VERSION 5.8 ;
BUSBITCHARS "[]" ;
DIVIDERCHAR "/" ;
UNITS
    DATABASE MICRONS 1000 ;
END UNITS

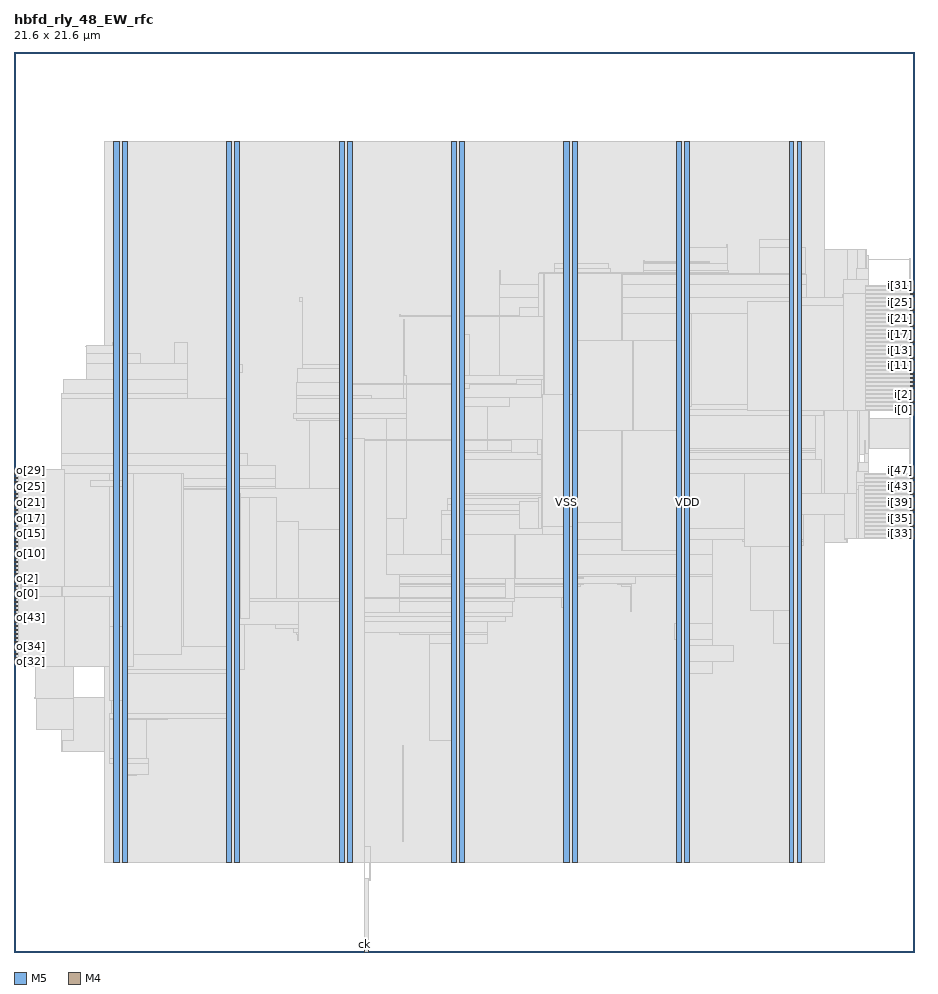
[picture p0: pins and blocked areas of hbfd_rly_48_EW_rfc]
MACRO hbfd_rly_48_EW_rfc
  FOREIGN hbfd_rly_48_EW_rfc 0 0 ;
  CLASS BLOCK ;
  SIZE 21.6 BY 21.6 ;
  PIN ck
    DIRECTION INPUT ;
    USE SIGNAL ;
    PORT
      LAYER M5 ;
        RECT  8.4 0 8.424 0.084 ;
    END
  END ck
  PIN i[0]
    DIRECTION INPUT ;
    USE SIGNAL ;
    PORT
      LAYER M4 ;
        RECT  21.516 13.008 21.6 13.032 ;
    END
  END i[0]
  PIN i[10]
    DIRECTION INPUT ;
    USE SIGNAL ;
    PORT
      LAYER M4 ;
        RECT  21.516 13.968 21.6 13.992 ;
    END
  END i[10]
  PIN i[11]
    DIRECTION INPUT ;
    USE SIGNAL ;
    PORT
      LAYER M4 ;
        RECT  21.516 14.064 21.6 14.088 ;
    END
  END i[11]
  PIN i[12]
    DIRECTION INPUT ;
    USE SIGNAL ;
    PORT
      LAYER M4 ;
        RECT  21.516 14.16 21.6 14.184 ;
    END
  END i[12]
  PIN i[13]
    DIRECTION INPUT ;
    USE SIGNAL ;
    PORT
      LAYER M4 ;
        RECT  21.516 14.256 21.6 14.28 ;
    END
  END i[13]
  PIN i[14]
    DIRECTION INPUT ;
    USE SIGNAL ;
    PORT
      LAYER M4 ;
        RECT  21.516 14.352 21.6 14.376 ;
    END
  END i[14]
  PIN i[15]
    DIRECTION INPUT ;
    USE SIGNAL ;
    PORT
      LAYER M4 ;
        RECT  21.516 14.448 21.6 14.472 ;
    END
  END i[15]
  PIN i[16]
    DIRECTION INPUT ;
    USE SIGNAL ;
    PORT
      LAYER M4 ;
        RECT  21.516 14.544 21.6 14.568 ;
    END
  END i[16]
  PIN i[17]
    DIRECTION INPUT ;
    USE SIGNAL ;
    PORT
      LAYER M4 ;
        RECT  21.516 14.64 21.6 14.664 ;
    END
  END i[17]
  PIN i[18]
    DIRECTION INPUT ;
    USE SIGNAL ;
    PORT
      LAYER M4 ;
        RECT  21.516 14.736 21.6 14.76 ;
    END
  END i[18]
  PIN i[19]
    DIRECTION INPUT ;
    USE SIGNAL ;
    PORT
      LAYER M4 ;
        RECT  21.516 14.832 21.6 14.856 ;
    END
  END i[19]
  PIN i[1]
    DIRECTION INPUT ;
    USE SIGNAL ;
    PORT
      LAYER M4 ;
        RECT  21.516 13.104 21.6 13.128 ;
    END
  END i[1]
  PIN i[20]
    DIRECTION INPUT ;
    USE SIGNAL ;
    PORT
      LAYER M4 ;
        RECT  21.516 14.928 21.6 14.952 ;
    END
  END i[20]
  PIN i[21]
    DIRECTION INPUT ;
    USE SIGNAL ;
    PORT
      LAYER M4 ;
        RECT  21.516 15.024 21.6 15.048 ;
    END
  END i[21]
  PIN i[22]
    DIRECTION INPUT ;
    USE SIGNAL ;
    PORT
      LAYER M4 ;
        RECT  21.516 15.12 21.6 15.144 ;
    END
  END i[22]
  PIN i[23]
    DIRECTION INPUT ;
    USE SIGNAL ;
    PORT
      LAYER M4 ;
        RECT  21.516 15.216 21.6 15.24 ;
    END
  END i[23]
  PIN i[24]
    DIRECTION INPUT ;
    USE SIGNAL ;
    PORT
      LAYER M4 ;
        RECT  21.516 15.312 21.6 15.336 ;
    END
  END i[24]
  PIN i[25]
    DIRECTION INPUT ;
    USE SIGNAL ;
    PORT
      LAYER M4 ;
        RECT  21.516 15.408 21.6 15.432 ;
    END
  END i[25]
  PIN i[26]
    DIRECTION INPUT ;
    USE SIGNAL ;
    PORT
      LAYER M4 ;
        RECT  21.516 15.504 21.6 15.528 ;
    END
  END i[26]
  PIN i[27]
    DIRECTION INPUT ;
    USE SIGNAL ;
    PORT
      LAYER M4 ;
        RECT  21.516 15.6 21.6 15.624 ;
    END
  END i[27]
  PIN i[28]
    DIRECTION INPUT ;
    USE SIGNAL ;
    PORT
      LAYER M4 ;
        RECT  21.516 15.696 21.6 15.72 ;
    END
  END i[28]
  PIN i[29]
    DIRECTION INPUT ;
    USE SIGNAL ;
    PORT
      LAYER M4 ;
        RECT  21.516 15.792 21.6 15.816 ;
    END
  END i[29]
  PIN i[2]
    DIRECTION INPUT ;
    USE SIGNAL ;
    PORT
      LAYER M4 ;
        RECT  21.516 13.2 21.6 13.224 ;
    END
  END i[2]
  PIN i[30]
    DIRECTION INPUT ;
    USE SIGNAL ;
    PORT
      LAYER M4 ;
        RECT  21.516 15.888 21.6 15.912 ;
    END
  END i[30]
  PIN i[31]
    DIRECTION INPUT ;
    USE SIGNAL ;
    PORT
      LAYER M4 ;
        RECT  21.516 15.984 21.6 16.008 ;
    END
  END i[31]
  PIN i[32]
    DIRECTION INPUT ;
    USE SIGNAL ;
    PORT
      LAYER M4 ;
        RECT  21.516 9.936 21.6 9.96 ;
    END
  END i[32]
  PIN i[33]
    DIRECTION INPUT ;
    USE SIGNAL ;
    PORT
      LAYER M4 ;
        RECT  21.516 10.032 21.6 10.056 ;
    END
  END i[33]
  PIN i[34]
    DIRECTION INPUT ;
    USE SIGNAL ;
    PORT
      LAYER M4 ;
        RECT  21.516 10.128 21.6 10.152 ;
    END
  END i[34]
  PIN i[35]
    DIRECTION INPUT ;
    USE SIGNAL ;
    PORT
      LAYER M4 ;
        RECT  21.516 10.224 21.6 10.248 ;
    END
  END i[35]
  PIN i[36]
    DIRECTION INPUT ;
    USE SIGNAL ;
    PORT
      LAYER M4 ;
        RECT  21.516 10.32 21.6 10.344 ;
    END
  END i[36]
  PIN i[37]
    DIRECTION INPUT ;
    USE SIGNAL ;
    PORT
      LAYER M4 ;
        RECT  21.516 10.416 21.6 10.44 ;
    END
  END i[37]
  PIN i[38]
    DIRECTION INPUT ;
    USE SIGNAL ;
    PORT
      LAYER M4 ;
        RECT  21.516 10.512 21.6 10.536 ;
    END
  END i[38]
  PIN i[39]
    DIRECTION INPUT ;
    USE SIGNAL ;
    PORT
      LAYER M4 ;
        RECT  21.516 10.608 21.6 10.632 ;
    END
  END i[39]
  PIN i[3]
    DIRECTION INPUT ;
    USE SIGNAL ;
    PORT
      LAYER M4 ;
        RECT  21.516 13.296 21.6 13.32 ;
    END
  END i[3]
  PIN i[40]
    DIRECTION INPUT ;
    USE SIGNAL ;
    PORT
      LAYER M4 ;
        RECT  21.516 10.704 21.6 10.728 ;
    END
  END i[40]
  PIN i[41]
    DIRECTION INPUT ;
    USE SIGNAL ;
    PORT
      LAYER M4 ;
        RECT  21.516 10.8 21.6 10.824 ;
    END
  END i[41]
  PIN i[42]
    DIRECTION INPUT ;
    USE SIGNAL ;
    PORT
      LAYER M4 ;
        RECT  21.516 10.896 21.6 10.92 ;
    END
  END i[42]
  PIN i[43]
    DIRECTION INPUT ;
    USE SIGNAL ;
    PORT
      LAYER M4 ;
        RECT  21.516 10.992 21.6 11.016 ;
    END
  END i[43]
  PIN i[44]
    DIRECTION INPUT ;
    USE SIGNAL ;
    PORT
      LAYER M4 ;
        RECT  21.516 11.088 21.6 11.112 ;
    END
  END i[44]
  PIN i[45]
    DIRECTION INPUT ;
    USE SIGNAL ;
    PORT
      LAYER M4 ;
        RECT  21.516 11.184 21.6 11.208 ;
    END
  END i[45]
  PIN i[46]
    DIRECTION INPUT ;
    USE SIGNAL ;
    PORT
      LAYER M4 ;
        RECT  21.516 11.28 21.6 11.304 ;
    END
  END i[46]
  PIN i[47]
    DIRECTION INPUT ;
    USE SIGNAL ;
    PORT
      LAYER M4 ;
        RECT  21.516 11.376 21.6 11.4 ;
    END
  END i[47]
  PIN i[4]
    DIRECTION INPUT ;
    USE SIGNAL ;
    PORT
      LAYER M4 ;
        RECT  21.516 13.392 21.6 13.416 ;
    END
  END i[4]
  PIN i[5]
    DIRECTION INPUT ;
    USE SIGNAL ;
    PORT
      LAYER M4 ;
        RECT  21.516 13.488 21.6 13.512 ;
    END
  END i[5]
  PIN i[6]
    DIRECTION INPUT ;
    USE SIGNAL ;
    PORT
      LAYER M4 ;
        RECT  21.516 13.584 21.6 13.608 ;
    END
  END i[6]
  PIN i[7]
    DIRECTION INPUT ;
    USE SIGNAL ;
    PORT
      LAYER M4 ;
        RECT  21.516 13.68 21.6 13.704 ;
    END
  END i[7]
  PIN i[8]
    DIRECTION INPUT ;
    USE SIGNAL ;
    PORT
      LAYER M4 ;
        RECT  21.516 13.776 21.6 13.8 ;
    END
  END i[8]
  PIN i[9]
    DIRECTION INPUT ;
    USE SIGNAL ;
    PORT
      LAYER M4 ;
        RECT  21.516 13.872 21.6 13.896 ;
    END
  END i[9]
  PIN o[0]
    DIRECTION OUTPUT ;
    USE SIGNAL ;
    PORT
      LAYER M4 ;
        RECT  0 8.592 0.084 8.616 ;
    END
  END o[0]
  PIN o[10]
    DIRECTION OUTPUT ;
    USE SIGNAL ;
    PORT
      LAYER M4 ;
        RECT  0 9.552 0.084 9.576 ;
    END
  END o[10]
  PIN o[11]
    DIRECTION OUTPUT ;
    USE SIGNAL ;
    PORT
      LAYER M4 ;
        RECT  0 9.648 0.084 9.672 ;
    END
  END o[11]
  PIN o[12]
    DIRECTION OUTPUT ;
    USE SIGNAL ;
    PORT
      LAYER M4 ;
        RECT  0 9.744 0.084 9.768 ;
    END
  END o[12]
  PIN o[13]
    DIRECTION OUTPUT ;
    USE SIGNAL ;
    PORT
      LAYER M4 ;
        RECT  0 9.84 0.084 9.864 ;
    END
  END o[13]
  PIN o[14]
    DIRECTION OUTPUT ;
    USE SIGNAL ;
    PORT
      LAYER M4 ;
        RECT  0 9.936 0.084 9.96 ;
    END
  END o[14]
  PIN o[15]
    DIRECTION OUTPUT ;
    USE SIGNAL ;
    PORT
      LAYER M4 ;
        RECT  0 10.032 0.084 10.056 ;
    END
  END o[15]
  PIN o[16]
    DIRECTION OUTPUT ;
    USE SIGNAL ;
    PORT
      LAYER M4 ;
        RECT  0 10.128 0.084 10.152 ;
    END
  END o[16]
  PIN o[17]
    DIRECTION OUTPUT ;
    USE SIGNAL ;
    PORT
      LAYER M4 ;
        RECT  0 10.224 0.084 10.248 ;
    END
  END o[17]
  PIN o[18]
    DIRECTION OUTPUT ;
    USE SIGNAL ;
    PORT
      LAYER M4 ;
        RECT  0 10.32 0.084 10.344 ;
    END
  END o[18]
  PIN o[19]
    DIRECTION OUTPUT ;
    USE SIGNAL ;
    PORT
      LAYER M4 ;
        RECT  0 10.416 0.084 10.44 ;
    END
  END o[19]
  PIN o[1]
    DIRECTION OUTPUT ;
    USE SIGNAL ;
    PORT
      LAYER M4 ;
        RECT  0 8.688 0.084 8.712 ;
    END
  END o[1]
  PIN o[20]
    DIRECTION OUTPUT ;
    USE SIGNAL ;
    PORT
      LAYER M4 ;
        RECT  0 10.512 0.084 10.536 ;
    END
  END o[20]
  PIN o[21]
    DIRECTION OUTPUT ;
    USE SIGNAL ;
    PORT
      LAYER M4 ;
        RECT  0 10.608 0.084 10.632 ;
    END
  END o[21]
  PIN o[22]
    DIRECTION OUTPUT ;
    USE SIGNAL ;
    PORT
      LAYER M4 ;
        RECT  0 10.704 0.084 10.728 ;
    END
  END o[22]
  PIN o[23]
    DIRECTION OUTPUT ;
    USE SIGNAL ;
    PORT
      LAYER M4 ;
        RECT  0 10.8 0.084 10.824 ;
    END
  END o[23]
  PIN o[24]
    DIRECTION OUTPUT ;
    USE SIGNAL ;
    PORT
      LAYER M4 ;
        RECT  0 10.896 0.084 10.92 ;
    END
  END o[24]
  PIN o[25]
    DIRECTION OUTPUT ;
    USE SIGNAL ;
    PORT
      LAYER M4 ;
        RECT  0 10.992 0.084 11.016 ;
    END
  END o[25]
  PIN o[26]
    DIRECTION OUTPUT ;
    USE SIGNAL ;
    PORT
      LAYER M4 ;
        RECT  0 11.088 0.084 11.112 ;
    END
  END o[26]
  PIN o[27]
    DIRECTION OUTPUT ;
    USE SIGNAL ;
    PORT
      LAYER M4 ;
        RECT  0 11.184 0.084 11.208 ;
    END
  END o[27]
  PIN o[28]
    DIRECTION OUTPUT ;
    USE SIGNAL ;
    PORT
      LAYER M4 ;
        RECT  0 11.28 0.084 11.304 ;
    END
  END o[28]
  PIN o[29]
    DIRECTION OUTPUT ;
    USE SIGNAL ;
    PORT
      LAYER M4 ;
        RECT  0 11.376 0.084 11.4 ;
    END
  END o[29]
  PIN o[2]
    DIRECTION OUTPUT ;
    USE SIGNAL ;
    PORT
      LAYER M4 ;
        RECT  0 8.784 0.084 8.808 ;
    END
  END o[2]
  PIN o[30]
    DIRECTION OUTPUT ;
    USE SIGNAL ;
    PORT
      LAYER M4 ;
        RECT  0 11.472 0.084 11.496 ;
    END
  END o[30]
  PIN o[31]
    DIRECTION OUTPUT ;
    USE SIGNAL ;
    PORT
      LAYER M4 ;
        RECT  0 11.568 0.084 11.592 ;
    END
  END o[31]
  PIN o[32]
    DIRECTION OUTPUT ;
    USE SIGNAL ;
    PORT
      LAYER M4 ;
        RECT  0 6.96 0.084 6.984 ;
    END
  END o[32]
  PIN o[33]
    DIRECTION OUTPUT ;
    USE SIGNAL ;
    PORT
      LAYER M4 ;
        RECT  0 7.056 0.084 7.08 ;
    END
  END o[33]
  PIN o[34]
    DIRECTION OUTPUT ;
    USE SIGNAL ;
    PORT
      LAYER M4 ;
        RECT  0 7.152 0.084 7.176 ;
    END
  END o[34]
  PIN o[35]
    DIRECTION OUTPUT ;
    USE SIGNAL ;
    PORT
      LAYER M4 ;
        RECT  0 7.248 0.084 7.272 ;
    END
  END o[35]
  PIN o[36]
    DIRECTION OUTPUT ;
    USE SIGNAL ;
    PORT
      LAYER M4 ;
        RECT  0 7.344 0.084 7.368 ;
    END
  END o[36]
  PIN o[37]
    DIRECTION OUTPUT ;
    USE SIGNAL ;
    PORT
      LAYER M4 ;
        RECT  0 7.44 0.084 7.464 ;
    END
  END o[37]
  PIN o[38]
    DIRECTION OUTPUT ;
    USE SIGNAL ;
    PORT
      LAYER M4 ;
        RECT  0 7.536 0.084 7.56 ;
    END
  END o[38]
  PIN o[39]
    DIRECTION OUTPUT ;
    USE SIGNAL ;
    PORT
      LAYER M4 ;
        RECT  0 7.632 0.084 7.656 ;
    END
  END o[39]
  PIN o[3]
    DIRECTION OUTPUT ;
    USE SIGNAL ;
    PORT
      LAYER M4 ;
        RECT  0 8.88 0.084 8.904 ;
    END
  END o[3]
  PIN o[40]
    DIRECTION OUTPUT ;
    USE SIGNAL ;
    PORT
      LAYER M4 ;
        RECT  0 7.728 0.084 7.752 ;
    END
  END o[40]
  PIN o[41]
    DIRECTION OUTPUT ;
    USE SIGNAL ;
    PORT
      LAYER M4 ;
        RECT  0 7.824 0.084 7.848 ;
    END
  END o[41]
  PIN o[42]
    DIRECTION OUTPUT ;
    USE SIGNAL ;
    PORT
      LAYER M4 ;
        RECT  0 7.92 0.084 7.944 ;
    END
  END o[42]
  PIN o[43]
    DIRECTION OUTPUT ;
    USE SIGNAL ;
    PORT
      LAYER M4 ;
        RECT  0 8.016 0.084 8.04 ;
    END
  END o[43]
  PIN o[44]
    DIRECTION OUTPUT ;
    USE SIGNAL ;
    PORT
      LAYER M4 ;
        RECT  0 8.112 0.084 8.136 ;
    END
  END o[44]
  PIN o[45]
    DIRECTION OUTPUT ;
    USE SIGNAL ;
    PORT
      LAYER M4 ;
        RECT  0 8.208 0.084 8.232 ;
    END
  END o[45]
  PIN o[46]
    DIRECTION OUTPUT ;
    USE SIGNAL ;
    PORT
      LAYER M4 ;
        RECT  0 8.304 0.084 8.328 ;
    END
  END o[46]
  PIN o[47]
    DIRECTION OUTPUT ;
    USE SIGNAL ;
    PORT
      LAYER M4 ;
        RECT  0 8.4 0.084 8.424 ;
    END
  END o[47]
  PIN o[4]
    DIRECTION OUTPUT ;
    USE SIGNAL ;
    PORT
      LAYER M4 ;
        RECT  0 8.976 0.084 9 ;
    END
  END o[4]
  PIN o[5]
    DIRECTION OUTPUT ;
    USE SIGNAL ;
    PORT
      LAYER M4 ;
        RECT  0 9.072 0.084 9.096 ;
    END
  END o[5]
  PIN o[6]
    DIRECTION OUTPUT ;
    USE SIGNAL ;
    PORT
      LAYER M4 ;
        RECT  0 9.168 0.084 9.192 ;
    END
  END o[6]
  PIN o[7]
    DIRECTION OUTPUT ;
    USE SIGNAL ;
    PORT
      LAYER M4 ;
        RECT  0 9.264 0.084 9.288 ;
    END
  END o[7]
  PIN o[8]
    DIRECTION OUTPUT ;
    USE SIGNAL ;
    PORT
      LAYER M4 ;
        RECT  0 9.36 0.084 9.384 ;
    END
  END o[8]
  PIN o[9]
    DIRECTION OUTPUT ;
    USE SIGNAL ;
    PORT
      LAYER M4 ;
        RECT  0 9.456 0.084 9.48 ;
    END
  END o[9]
  PIN rfi
    DIRECTION INPUT ;
    USE SIGNAL ;
    PORT
      LAYER M4 ;
        RECT  21.516 11.472 21.6 11.496 ;
    END
  END rfi
  PIN rfo
    DIRECTION OUTPUT ;
    USE SIGNAL ;
    PORT
      LAYER M4 ;
        RECT  0 8.496 0.084 8.52 ;
    END
  END rfo
  PIN rs
    DIRECTION INPUT ;
    USE SIGNAL ;
    PORT
      LAYER M5 ;
        RECT  8.496 0 8.52 0.084 ;
    END
  END rs
  PIN VDD
    DIRECTION INOUT ;
    USE POWER ;
    PORT
      LAYER M5 ;
        RECT  18.792 2.151 18.912 19.449 ;
        RECT  16.092 2.151 16.212 19.449 ;
        RECT  13.392 2.151 13.512 19.449 ;
        RECT  10.692 2.151 10.812 19.449 ;
        RECT  7.992 2.151 8.112 19.449 ;
        RECT  5.292 2.151 5.412 19.449 ;
        RECT  2.592 2.151 2.712 19.449 ;
    END
  END VDD
  PIN VSS
    DIRECTION INOUT ;
    USE GROUND ;
    PORT
      LAYER M5 ;
        RECT  18.6 2.137 18.72 19.463 ;
        RECT  15.9 2.137 16.02 19.463 ;
        RECT  13.2 2.137 13.32 19.463 ;
        RECT  10.5 2.137 10.62 19.463 ;
        RECT  7.8 2.137 7.92 19.463 ;
        RECT  5.1 2.137 5.22 19.463 ;
        RECT  2.4 2.137 2.52 19.463 ;
    END
  END VSS
  # OT_OBS_CLOSED layer=M5 d_um=1.536 added=8
  OBS
    LAYER RVTN ;
     RECT  2.16 2.16 19.44 2.295 ;
     RECT  2.16 2.565 19.44 2.835 ;
     RECT  2.16 3.105 19.44 3.375 ;
     RECT  2.16 3.645 19.44 3.915 ;
     RECT  2.16 4.185 19.44 4.455 ;
     RECT  2.16 4.725 19.44 4.995 ;
     RECT  2.16 5.265 19.44 5.535 ;
     RECT  2.16 5.805 19.44 6.075 ;
     RECT  2.16 6.345 19.44 6.615 ;
     RECT  2.16 6.885 19.44 7.155 ;
     RECT  2.16 7.425 19.44 7.695 ;
     RECT  2.16 7.965 19.44 8.235 ;
     RECT  2.16 8.505 19.44 8.775 ;
     RECT  2.16 9.045 19.44 9.315 ;
     RECT  2.16 9.585 19.44 9.855 ;
     RECT  2.16 10.125 19.44 10.395 ;
     RECT  2.16 10.665 19.44 10.935 ;
     RECT  2.16 11.205 19.44 11.475 ;
     RECT  2.16 11.745 19.44 12.015 ;
     RECT  2.16 12.285 19.44 12.555 ;
     RECT  2.16 12.825 19.44 13.095 ;
     RECT  2.16 13.365 19.44 13.635 ;
     RECT  2.16 13.905 19.44 14.175 ;
     RECT  2.16 14.445 19.44 14.715 ;
     RECT  2.16 14.985 19.44 15.255 ;
     RECT  2.16 15.525 19.44 15.795 ;
     RECT  2.16 16.065 19.44 16.335 ;
     RECT  2.16 16.605 19.44 16.875 ;
     RECT  2.16 17.145 19.44 17.415 ;
     RECT  2.16 17.685 19.44 17.955 ;
     RECT  2.16 18.225 19.44 18.495 ;
     RECT  2.16 18.765 19.44 19.035 ;
     RECT  2.16 19.305 19.44 19.44 ;
    LAYER RVTP ;
     RECT  2.16 2.295 19.44 2.565 ;
     RECT  2.16 2.835 19.44 3.105 ;
     RECT  2.16 3.375 19.44 3.645 ;
     RECT  2.16 3.915 19.44 4.185 ;
     RECT  2.16 4.455 19.44 4.725 ;
     RECT  2.16 4.995 19.44 5.265 ;
     RECT  2.16 5.535 19.44 5.805 ;
     RECT  2.16 6.075 19.44 6.345 ;
     RECT  2.16 6.615 19.44 6.885 ;
     RECT  2.16 7.155 19.44 7.425 ;
     RECT  2.16 7.695 19.44 7.965 ;
     RECT  2.16 8.235 19.44 8.505 ;
     RECT  2.16 8.775 19.44 9.045 ;
     RECT  2.16 9.315 19.44 9.585 ;
     RECT  2.16 9.855 19.44 10.125 ;
     RECT  2.16 10.395 19.44 10.665 ;
     RECT  2.16 10.935 19.44 11.205 ;
     RECT  2.16 11.475 19.44 11.745 ;
     RECT  2.16 12.015 19.44 12.285 ;
     RECT  2.16 12.555 19.44 12.825 ;
     RECT  2.16 13.095 19.44 13.365 ;
     RECT  2.16 13.635 19.44 13.905 ;
     RECT  2.16 14.175 19.44 14.445 ;
     RECT  2.16 14.715 19.44 14.985 ;
     RECT  2.16 15.255 19.44 15.525 ;
     RECT  2.16 15.795 19.44 16.065 ;
     RECT  2.16 16.335 19.44 16.605 ;
     RECT  2.16 16.875 19.44 17.145 ;
     RECT  2.16 17.415 19.44 17.685 ;
     RECT  2.16 17.955 19.44 18.225 ;
     RECT  2.16 18.495 19.44 18.765 ;
     RECT  2.16 19.035 19.44 19.305 ;
    LAYER M1 ;
     RECT  2.16 2.151 19.44 19.449 ;
    LAYER M2 ;
     RECT  0.103 8.208 0.139 8.496 ;
     RECT  0.103 10.836 0.203 10.854 ;
     RECT  0.139 8.136 0.239 8.874 ;
     RECT  0.319 9.486 0.419 9.504 ;
     RECT  0.499 6.084 0.535 6.102 ;
     RECT  0.535 5.346 1.147 6.102 ;
     RECT  1.147 13.374 1.183 13.392 ;
     RECT  0.239 8.136 1.255 8.496 ;
     RECT  1.399 12.366 1.471 12.384 ;
     RECT  1.147 4.806 2.16 6.102 ;
     RECT  1.255 7.668 2.16 8.496 ;
     RECT  1.471 12.33 2.16 12.384 ;
     RECT  1.183 13.374 2.16 13.734 ;
     RECT  1.723 14.526 2.16 14.544 ;
     RECT  2.16 2.151 19.44 19.449 ;
     RECT  19.44 9.828 20.003 16.866 ;
     RECT  20.003 10.098 20.255 16.866 ;
     RECT  20.255 10.098 20.291 13.086 ;
     RECT  20.291 10.098 20.435 11.196 ;
     RECT  20.255 14.148 20.435 16.866 ;
     RECT  20.435 10.17 20.471 10.926 ;
     RECT  20.435 16.614 20.471 16.866 ;
     RECT  20.471 10.17 20.507 10.386 ;
     RECT  20.291 11.952 20.507 13.086 ;
     RECT  20.435 14.148 20.507 14.976 ;
     RECT  20.471 16.614 20.507 16.704 ;
     RECT  20.507 12.096 20.543 13.086 ;
     RECT  20.543 12.096 21.515 12.816 ;
     RECT  20.507 16.614 21.515 16.632 ;
    LAYER M3 ;
     RECT  8.532 1.723 8.55 2.143 ;
     RECT  2.415 2.143 2.505 2.413 ;
     RECT  5.115 2.143 5.205 2.413 ;
     RECT  10.515 2.143 10.605 2.413 ;
     RECT  13.215 2.143 13.305 2.413 ;
     RECT  15.915 2.143 16.005 2.413 ;
     RECT  18.615 2.143 18.705 2.413 ;
     RECT  7.815 2.143 8.55 2.525 ;
     RECT  2.415 2.413 2.697 4.225 ;
     RECT  2.415 4.225 2.934 4.261 ;
     RECT  2.415 4.261 3.222 4.531 ;
     RECT  2.304 4.531 3.222 4.649 ;
     RECT  9.324 2.641 9.342 4.955 ;
     RECT  1.152 4.801 1.17 5.071 ;
     RECT  10.515 2.413 10.797 5.071 ;
     RECT  1.152 5.071 1.422 5.341 ;
     RECT  2.304 4.649 3.186 5.575 ;
     RECT  2.304 5.575 3.69 5.611 ;
     RECT  5.115 2.413 5.397 5.611 ;
     RECT  2.304 5.611 5.397 5.729 ;
     RECT  0.54 5.341 1.422 6.079 ;
     RECT  2.34 5.729 5.397 6.691 ;
     RECT  15.915 2.413 16.197 6.691 ;
     RECT  2.304 6.691 5.397 6.781 ;
     RECT  0.504 6.079 1.422 6.859 ;
     RECT  15.915 6.691 16.758 6.961 ;
     RECT  0.108 6.859 1.422 6.989 ;
     RECT  0.504 6.989 1.422 7.277 ;
     RECT  15.915 6.961 17.262 7.349 ;
     RECT  9.972 5.071 10.797 7.393 ;
     RECT  18.615 2.413 18.897 7.393 ;
     RECT  15.915 7.349 16.758 7.501 ;
     RECT  6.804 7.465 6.822 7.627 ;
     RECT  9.972 7.393 11.358 7.627 ;
     RECT  1.26 7.277 1.422 7.663 ;
     RECT  6.768 7.627 6.822 7.663 ;
     RECT  7.815 2.525 8.097 7.663 ;
     RECT  9.252 7.627 11.358 7.663 ;
     RECT  1.26 7.663 1.458 7.709 ;
     RECT  6.696 7.663 6.822 7.771 ;
     RECT  0.504 7.277 0.522 7.853 ;
     RECT  2.304 6.781 5.526 7.861 ;
     RECT  6.264 7.771 6.822 7.861 ;
     RECT  15.84 7.501 16.758 7.889 ;
     RECT  7.815 7.663 11.358 7.933 ;
     RECT  7.815 7.933 11.79 8.041 ;
     RECT  7.815 8.041 11.97 8.159 ;
     RECT  0.144 8.107 0.198 8.188 ;
     RECT  18.216 7.393 18.897 8.203 ;
     RECT  1.26 7.709 1.422 8.251 ;
     RECT  13.215 2.413 13.497 8.275 ;
     RECT  2.304 7.861 6.822 8.401 ;
     RECT  7.815 8.159 8.097 8.401 ;
     RECT  9.252 8.159 11.97 8.401 ;
     RECT  1.152 8.251 1.422 8.477 ;
     RECT  9.252 8.401 12.006 8.509 ;
     RECT  13.14 8.275 13.497 8.509 ;
     RECT  1.26 8.477 1.422 8.621 ;
     RECT  0.108 8.188 0.198 8.683 ;
     RECT  9.252 8.509 13.497 8.779 ;
     RECT  14.796 8.167 14.814 8.779 ;
     RECT  1.26 8.621 1.278 8.813 ;
     RECT  9.252 8.779 13.59 8.815 ;
     RECT  14.58 8.779 14.814 8.815 ;
     RECT  9.252 8.815 13.662 8.851 ;
     RECT  14.472 8.815 14.814 8.851 ;
     RECT  9.252 8.851 14.922 9.013 ;
     RECT  15.915 7.889 16.758 9.013 ;
     RECT  9.252 9.013 16.758 9.049 ;
     RECT  2.304 8.401 8.097 9.163 ;
     RECT  2.268 9.163 8.097 9.239 ;
     RECT  0.108 8.683 0.342 9.481 ;
     RECT  0.108 9.481 0.414 9.533 ;
     RECT  8.928 9.049 16.758 9.545 ;
     RECT  0.108 9.533 0.342 9.581 ;
     RECT  0.324 9.581 0.342 9.677 ;
     RECT  17.676 8.203 18.897 9.739 ;
     RECT  17.532 9.739 18.897 9.751 ;
     RECT  17.532 9.751 18.954 9.859 ;
     RECT  10.26 9.545 16.758 9.895 ;
     RECT  17.496 9.859 18.954 9.895 ;
     RECT  19.98 9.823 19.998 9.895 ;
     RECT  19.944 9.895 19.998 10.027 ;
     RECT  19.944 10.027 20.43 10.123 ;
     RECT  1.404 9.931 1.422 10.219 ;
     RECT  19.944 10.123 20.502 10.391 ;
     RECT  8.928 9.545 9.342 10.399 ;
     RECT  10.26 9.895 18.954 10.507 ;
     RECT  19.944 10.391 20.466 10.507 ;
     RECT  10.26 10.507 20.466 10.589 ;
     RECT  10.404 10.589 20.466 10.733 ;
     RECT  0.144 10.651 0.162 10.828 ;
     RECT  10.404 10.733 19.494 10.895 ;
     RECT  10.515 10.895 19.494 10.967 ;
     RECT  10.515 10.967 19.422 11.003 ;
     RECT  0.108 10.828 0.198 11.117 ;
     RECT  2.304 9.239 8.097 11.129 ;
     RECT  0.18 11.117 0.198 11.165 ;
     RECT  1.404 10.219 1.494 11.179 ;
     RECT  2.304 11.129 6.282 11.179 ;
     RECT  20.232 10.733 20.466 11.275 ;
     RECT  1.404 11.179 6.282 11.371 ;
     RECT  20.232 11.275 20.502 11.543 ;
     RECT  1.152 11.371 6.282 11.669 ;
     RECT  20.268 11.543 20.502 11.741 ;
     RECT  10.515 11.003 19.386 11.813 ;
     RECT  1.152 11.669 5.598 11.975 ;
     RECT  20.412 11.741 20.502 11.975 ;
     RECT  10.515 11.813 19.242 11.981 ;
     RECT  10.515 11.981 11.97 12.029 ;
     RECT  12.744 11.981 19.242 12.047 ;
     RECT  12.816 12.047 19.242 12.083 ;
     RECT  20.412 11.975 20.43 12.281 ;
     RECT  7.092 11.129 8.097 12.757 ;
     RECT  6.768 12.757 8.097 12.793 ;
     RECT  8.928 10.399 9.414 12.793 ;
     RECT  13.104 12.083 19.242 12.865 ;
     RECT  6.696 12.793 9.414 12.929 ;
     RECT  13.104 12.865 19.422 13.027 ;
     RECT  10.515 12.029 11.358 13.099 ;
     RECT  21.492 11.371 21.51 13.133 ;
     RECT  12.924 13.027 19.422 13.147 ;
     RECT  20.52 13.063 20.538 13.195 ;
     RECT  1.152 11.975 5.397 13.289 ;
     RECT  6.768 12.929 9.414 13.289 ;
     RECT  12.744 13.147 19.422 13.291 ;
     RECT  20.232 13.195 20.538 13.291 ;
     RECT  10.515 13.099 11.898 13.297 ;
     RECT  12.744 13.291 20.538 13.297 ;
     RECT  6.768 13.289 8.586 13.361 ;
     RECT  1.152 13.289 4.158 13.397 ;
     RECT  10.515 13.297 20.538 13.613 ;
     RECT  6.768 13.361 8.097 13.667 ;
     RECT  1.188 13.397 4.158 13.739 ;
     RECT  9.36 13.289 9.414 13.829 ;
     RECT  10.515 13.613 20.502 13.829 ;
     RECT  5.115 13.289 5.397 13.909 ;
     RECT  6.804 13.667 8.097 14.009 ;
     RECT  5.115 13.909 5.49 14.099 ;
     RECT  6.912 14.009 8.097 14.099 ;
     RECT  1.728 13.739 4.158 14.135 ;
     RECT  1.728 14.135 3.042 14.369 ;
     RECT  1.728 14.369 2.697 14.549 ;
     RECT  2.376 14.549 2.697 14.639 ;
     RECT  3.852 14.135 4.158 14.639 ;
     RECT  10.515 13.829 10.926 14.819 ;
     RECT  9.36 13.829 9.378 15.179 ;
     RECT  9.252 15.259 9.27 15.296 ;
     RECT  6.912 14.099 6.93 15.601 ;
     RECT  6.84 15.601 6.93 15.719 ;
     RECT  11.664 13.829 20.502 15.719 ;
     RECT  19.872 15.719 20.502 15.791 ;
     RECT  11.664 15.719 19.026 16.025 ;
     RECT  19.908 15.791 20.502 16.133 ;
     RECT  12.6 16.025 19.026 16.259 ;
     RECT  12.6 16.259 18.99 16.295 ;
     RECT  12.6 16.295 17.154 16.301 ;
     RECT  11.664 16.025 11.682 16.367 ;
     RECT  15.12 16.301 17.154 16.367 ;
     RECT  12.96 16.301 14.31 16.403 ;
     RECT  20.232 16.133 20.502 16.403 ;
     RECT  12.96 16.403 14.274 16.529 ;
     RECT  15.12 16.367 17.118 16.529 ;
     RECT  15.12 16.529 15.138 16.589 ;
     RECT  21.492 15.883 21.51 16.637 ;
     RECT  20.448 16.403 20.502 16.709 ;
     RECT  20.448 16.709 20.466 16.871 ;
     RECT  15.915 16.529 17.118 16.907 ;
     RECT  17.892 16.295 18.99 16.907 ;
     RECT  17.1 16.907 17.118 16.979 ;
     RECT  17.892 16.907 18.897 17.105 ;
     RECT  2.415 14.639 2.697 19.187 ;
     RECT  5.115 14.099 5.397 19.187 ;
     RECT  7.815 14.099 8.097 19.187 ;
     RECT  10.515 14.819 10.797 19.187 ;
     RECT  13.215 16.529 13.497 19.187 ;
     RECT  15.915 16.907 16.197 19.187 ;
     RECT  18.615 17.105 18.897 19.187 ;
     RECT  2.415 19.187 2.505 19.457 ;
     RECT  5.115 19.187 5.205 19.457 ;
     RECT  7.815 19.187 7.905 19.457 ;
     RECT  10.515 19.187 10.605 19.457 ;
     RECT  13.215 19.187 13.305 19.457 ;
     RECT  15.915 19.187 16.005 19.457 ;
     RECT  18.615 19.187 18.705 19.457 ;
    LAYER M4 ;
     RECT  0.084 6.96 0.097 6.984 ;
     RECT  0.06 6.984 0.097 7.056 ;
     RECT  0.084 7.056 0.097 7.08 ;
     RECT  0.06 7.08 0.097 7.152 ;
     RECT  0.084 7.152 0.097 7.176 ;
     RECT  0.06 7.176 0.097 7.248 ;
     RECT  0.084 7.248 0.097 7.272 ;
     RECT  0.06 7.272 0.097 7.344 ;
     RECT  0.084 7.344 0.097 7.368 ;
     RECT  0.06 7.368 0.097 7.44 ;
     RECT  0.084 7.44 0.097 7.464 ;
     RECT  0.06 7.464 0.097 7.536 ;
     RECT  0.084 7.536 0.097 7.56 ;
     RECT  0.06 7.56 0.097 7.632 ;
     RECT  0.084 7.632 0.097 7.656 ;
     RECT  0.06 7.656 0.097 7.728 ;
     RECT  0.084 7.728 0.097 7.752 ;
     RECT  0.06 7.752 0.097 7.824 ;
     RECT  0.084 7.824 0.097 7.848 ;
     RECT  0.06 7.848 0.097 7.92 ;
     RECT  0.084 7.92 0.097 7.944 ;
     RECT  0.06 7.944 0.097 8.016 ;
     RECT  0.084 8.016 0.097 8.04 ;
     RECT  0.06 8.04 0.097 8.112 ;
     RECT  0.084 8.112 0.097 8.136 ;
     RECT  0.06 8.136 0.097 8.208 ;
     RECT  0.084 8.208 0.097 8.232 ;
     RECT  0.06 8.232 0.097 8.304 ;
     RECT  0.084 8.304 0.097 8.328 ;
     RECT  0.06 8.328 0.097 8.4 ;
     RECT  0.084 8.4 0.097 8.424 ;
     RECT  0.06 8.424 0.097 8.496 ;
     RECT  0.084 8.496 0.097 8.52 ;
     RECT  0.06 8.52 0.097 8.592 ;
     RECT  0.084 8.592 0.097 8.616 ;
     RECT  0.06 8.616 0.097 8.688 ;
     RECT  0.084 8.688 0.097 8.712 ;
     RECT  0.06 8.712 0.097 8.784 ;
     RECT  0.084 8.784 0.097 8.808 ;
     RECT  0.06 8.808 0.097 8.88 ;
     RECT  0.084 8.88 0.097 8.904 ;
     RECT  0.06 8.904 0.097 8.976 ;
     RECT  0.084 8.976 0.097 9 ;
     RECT  0.06 9 0.097 9.072 ;
     RECT  0.084 9.072 0.097 9.096 ;
     RECT  0.06 9.096 0.097 9.168 ;
     RECT  0.084 9.168 0.097 9.192 ;
     RECT  0.06 9.192 0.097 9.264 ;
     RECT  0.084 9.264 0.097 9.288 ;
     RECT  0.06 9.288 0.097 9.36 ;
     RECT  0.084 9.36 0.097 9.384 ;
     RECT  0.06 9.384 0.097 9.456 ;
     RECT  0.084 9.456 0.097 9.48 ;
     RECT  0.06 9.48 0.097 9.552 ;
     RECT  0.084 9.552 0.097 9.576 ;
     RECT  0.06 9.576 0.097 9.648 ;
     RECT  0.084 9.648 0.097 9.672 ;
     RECT  0.06 9.672 0.097 9.744 ;
     RECT  0.084 9.744 0.097 9.768 ;
     RECT  0.06 9.768 0.097 9.84 ;
     RECT  0.084 9.84 0.097 9.864 ;
     RECT  0.06 9.864 0.097 9.936 ;
     RECT  0.084 9.936 0.097 9.96 ;
     RECT  0.06 9.96 0.097 10.032 ;
     RECT  0.084 10.032 0.097 10.056 ;
     RECT  0.06 10.056 0.097 10.128 ;
     RECT  0.084 10.128 0.097 10.152 ;
     RECT  0.06 10.152 0.097 10.224 ;
     RECT  0.084 10.224 0.097 10.248 ;
     RECT  0.06 10.248 0.097 10.32 ;
     RECT  0.084 10.32 0.097 10.344 ;
     RECT  0.06 10.344 0.097 10.416 ;
     RECT  0.084 10.416 0.097 10.44 ;
     RECT  0.06 10.44 0.097 10.512 ;
     RECT  0.084 10.512 0.097 10.536 ;
     RECT  0.06 10.536 0.097 10.608 ;
     RECT  0.084 10.608 0.097 10.632 ;
     RECT  0.06 10.632 0.097 10.704 ;
     RECT  0.084 10.704 0.097 10.728 ;
     RECT  0.06 10.728 0.097 10.8 ;
     RECT  0.084 10.8 0.097 10.824 ;
     RECT  0.06 10.824 0.097 10.896 ;
     RECT  0.084 10.896 0.097 10.92 ;
     RECT  0.06 10.92 0.097 10.992 ;
     RECT  0.084 10.992 0.097 11.016 ;
     RECT  0.06 11.016 0.097 11.088 ;
     RECT  0.084 11.088 0.097 11.112 ;
     RECT  0.06 11.112 0.097 11.184 ;
     RECT  0.084 11.184 0.097 11.208 ;
     RECT  0.06 11.208 0.097 11.28 ;
     RECT  0.084 11.28 0.097 11.304 ;
     RECT  0.06 11.304 0.097 11.376 ;
     RECT  0.084 11.376 0.097 11.4 ;
     RECT  0.06 11.4 0.097 11.472 ;
     RECT  0.084 11.472 0.097 11.496 ;
     RECT  0.06 11.496 0.097 11.568 ;
     RECT  0.084 11.568 0.097 11.592 ;
     RECT  0.097 6.864 1.217 11.592 ;
     RECT  1.217 6.864 2.293 11.496 ;
     RECT  2.293 6.048 2.408 11.496 ;
     RECT  2.408 2.148 2.512 19.452 ;
     RECT  2.512 2.418 2.704 19.182 ;
     RECT  2.704 6.864 2.873 11.496 ;
     RECT  2.873 7.152 4.025 11.496 ;
     RECT  4.025 7.344 4.061 11.496 ;
     RECT  4.061 7.344 5.108 11.112 ;
     RECT  5.108 2.148 5.212 19.452 ;
     RECT  5.212 2.418 5.404 19.182 ;
     RECT  5.404 8.016 5.429 11.016 ;
     RECT  5.429 8.016 5.645 10.92 ;
     RECT  5.645 8.496 6.293 10.92 ;
     RECT  6.293 8.496 6.833 10.344 ;
     RECT  6.833 8.496 7.808 10.152 ;
     RECT  7.808 2.148 7.912 19.452 ;
     RECT  7.912 2.148 8.104 19.182 ;
     RECT  8.477 1.728 8.561 1.752 ;
     RECT  8.104 8.496 10.508 8.52 ;
     RECT  8.104 12.288 10.508 12.312 ;
     RECT  8.104 13.632 10.508 13.656 ;
     RECT  9.241 15.264 10.508 15.288 ;
     RECT  10.508 2.148 10.612 19.452 ;
     RECT  10.612 2.418 10.804 19.182 ;
     RECT  10.804 13.536 10.937 13.656 ;
     RECT  10.804 8.496 11.797 8.52 ;
     RECT  10.804 12.288 11.941 12.312 ;
     RECT  11.797 8.496 12.017 9 ;
     RECT  11.948 9.984 12.035 10.008 ;
     RECT  10.937 13.632 12.049 13.656 ;
     RECT  10.804 15.264 12.121 15.288 ;
     RECT  11.941 12 12.553 12.312 ;
     RECT  12.121 10.176 12.589 10.824 ;
     RECT  12.121 15.264 12.589 15.48 ;
     RECT  12.589 10.176 12.661 10.92 ;
     RECT  12.553 11.952 12.661 12.312 ;
     RECT  12.049 13.632 12.661 13.752 ;
     RECT  12.661 13.344 12.697 13.752 ;
     RECT  12.589 15.264 12.697 16.296 ;
     RECT  12.661 10.176 12.733 12.312 ;
     RECT  12.697 13.344 12.733 16.296 ;
     RECT  12.017 8.976 13.208 9 ;
     RECT  12.733 10.176 13.208 16.296 ;
     RECT  13.208 2.148 13.312 19.452 ;
     RECT  13.312 2.418 13.504 19.182 ;
     RECT  13.504 8.976 13.673 9 ;
     RECT  13.504 10.32 14.569 16.296 ;
     RECT  14.569 9.648 14.609 16.296 ;
     RECT  14.609 9.648 15.908 15.336 ;
     RECT  15.109 16.56 15.908 16.584 ;
     RECT  15.908 2.148 16.012 19.452 ;
     RECT  16.012 2.418 16.204 19.182 ;
     RECT  16.204 13.104 16.265 15.336 ;
     RECT  16.204 16.56 16.697 16.584 ;
     RECT  16.204 10.176 17.521 11.496 ;
     RECT  16.265 13.152 17.593 15.336 ;
     RECT  17.521 9.744 18.608 11.496 ;
     RECT  17.593 13.008 18.608 15.624 ;
     RECT  18.608 2.148 18.712 19.452 ;
     RECT  18.712 2.418 18.904 19.182 ;
     RECT  18.904 13.008 19.897 15.528 ;
     RECT  18.904 10.512 19.933 11.016 ;
     RECT  19.933 9.936 20.221 11.016 ;
     RECT  20.221 9.936 20.257 11.112 ;
     RECT  20.257 9.936 20.401 11.208 ;
     RECT  19.897 13.008 20.437 15.816 ;
     RECT  20.401 9.936 21.516 9.96 ;
     RECT  20.401 9.96 21.564 10.032 ;
     RECT  20.401 10.032 21.516 10.056 ;
     RECT  20.401 10.056 21.564 10.128 ;
     RECT  20.401 10.128 21.516 10.152 ;
     RECT  20.401 10.152 21.564 10.224 ;
     RECT  20.401 10.224 21.516 10.248 ;
     RECT  20.401 10.248 21.564 10.32 ;
     RECT  20.401 10.32 21.516 10.344 ;
     RECT  20.401 10.344 21.564 10.416 ;
     RECT  20.401 10.416 21.516 10.44 ;
     RECT  20.401 10.44 21.564 10.512 ;
     RECT  20.401 10.512 21.516 10.536 ;
     RECT  20.401 10.536 21.564 10.608 ;
     RECT  20.401 10.608 21.516 10.632 ;
     RECT  20.401 10.632 21.564 10.704 ;
     RECT  20.401 10.704 21.516 10.728 ;
     RECT  20.401 10.728 21.564 10.8 ;
     RECT  20.401 10.8 21.516 10.824 ;
     RECT  20.401 10.824 21.564 10.896 ;
     RECT  20.401 10.896 21.516 10.92 ;
     RECT  20.401 10.92 21.564 10.992 ;
     RECT  20.401 10.992 21.516 11.016 ;
     RECT  20.401 11.016 21.564 11.088 ;
     RECT  20.401 11.088 21.516 11.112 ;
     RECT  20.401 11.112 21.564 11.184 ;
     RECT  20.401 11.184 21.516 11.208 ;
     RECT  20.401 11.208 21.564 11.28 ;
     RECT  20.401 11.28 21.516 11.304 ;
     RECT  20.401 11.304 21.564 11.376 ;
     RECT  20.401 11.376 21.516 11.4 ;
     RECT  20.401 11.4 21.564 11.472 ;
     RECT  20.401 11.472 21.516 11.496 ;
     RECT  20.437 13.008 21.516 13.032 ;
     RECT  20.437 13.032 21.564 13.104 ;
     RECT  20.437 13.104 21.516 13.128 ;
     RECT  20.437 13.128 21.564 13.2 ;
     RECT  20.437 13.2 21.516 13.224 ;
     RECT  20.437 13.224 21.564 13.296 ;
     RECT  20.437 13.296 21.516 13.32 ;
     RECT  20.437 13.32 21.564 13.392 ;
     RECT  20.437 13.392 21.516 13.416 ;
     RECT  20.437 13.416 21.564 13.488 ;
     RECT  20.437 13.488 21.516 13.512 ;
     RECT  20.437 13.512 21.564 13.584 ;
     RECT  20.437 13.584 21.516 13.608 ;
     RECT  20.437 13.608 21.564 13.68 ;
     RECT  20.437 13.68 21.516 13.704 ;
     RECT  20.437 13.704 21.564 13.776 ;
     RECT  20.437 13.776 21.516 13.8 ;
     RECT  20.437 13.8 21.564 13.872 ;
     RECT  20.437 13.872 21.516 13.896 ;
     RECT  20.437 13.896 21.564 13.968 ;
     RECT  20.437 13.968 21.516 13.992 ;
     RECT  20.437 13.992 21.564 14.064 ;
     RECT  20.437 14.064 21.516 14.088 ;
     RECT  20.437 14.088 21.564 14.16 ;
     RECT  20.437 14.16 21.516 14.184 ;
     RECT  20.437 14.184 21.564 14.256 ;
     RECT  20.437 14.256 21.516 14.28 ;
     RECT  20.437 14.28 21.564 14.352 ;
     RECT  20.437 14.352 21.516 14.376 ;
     RECT  20.437 14.376 21.564 14.448 ;
     RECT  20.437 14.448 21.516 14.472 ;
     RECT  20.437 14.472 21.564 14.544 ;
     RECT  20.437 14.544 21.516 14.568 ;
     RECT  20.437 14.568 21.564 14.64 ;
     RECT  20.437 14.64 21.516 14.664 ;
     RECT  20.437 14.664 21.564 14.736 ;
     RECT  20.437 14.736 21.516 14.76 ;
     RECT  20.437 14.76 21.564 14.832 ;
     RECT  20.437 14.832 21.516 14.856 ;
     RECT  20.437 14.856 21.564 14.928 ;
     RECT  20.437 14.928 21.516 14.952 ;
     RECT  20.437 14.952 21.564 15.024 ;
     RECT  20.437 15.024 21.516 15.048 ;
     RECT  20.437 15.048 21.564 15.12 ;
     RECT  20.437 15.12 21.516 15.144 ;
     RECT  20.437 15.144 21.564 15.216 ;
     RECT  20.437 15.216 21.516 15.24 ;
     RECT  20.437 15.24 21.564 15.312 ;
     RECT  20.437 15.312 21.516 15.336 ;
     RECT  20.437 15.336 21.564 15.408 ;
     RECT  20.437 15.408 21.516 15.432 ;
     RECT  20.437 15.432 21.564 15.504 ;
     RECT  20.437 15.504 21.516 15.528 ;
     RECT  20.437 15.528 21.564 15.6 ;
     RECT  20.437 15.6 21.516 15.624 ;
     RECT  20.437 15.624 21.564 15.696 ;
     RECT  20.437 15.696 21.516 15.72 ;
     RECT  20.437 15.72 21.564 15.792 ;
     RECT  20.437 15.792 21.516 15.816 ;
     RECT  20.437 15.816 21.564 15.888 ;
     RECT  20.437 15.888 21.516 15.912 ;
     RECT  20.437 15.912 21.564 15.984 ;
     RECT  20.437 15.984 21.516 16.008 ;
    LAYER M5 ;
     RECT  8.424 0.016 8.496 0.084 ;
     RECT  8.4 0.084 8.52 1.763 ;
     RECT  8.4 1.763 8.424 2.137 ;
     RECT  2.4 2.137 2.52 2.151 ;
     RECT  5.1 2.137 5.22 2.151 ;
     RECT  10.5 2.137 10.62 2.151 ;
     RECT  13.2 2.137 13.32 2.151 ;
     RECT  15.9 2.137 16.02 2.151 ;
     RECT  18.6 2.137 18.72 2.151 ;
     RECT  2.4 2.151 2.712 6.037 ;
     RECT  2.304 6.037 2.712 7.811 ;
     RECT  1.152 8.533 1.176 8.771 ;
     RECT  0.144 8.533 0.168 8.819 ;
     RECT  12 8.965 12.024 10.019 ;
     RECT  13.2 2.151 13.512 10.213 ;
     RECT  2.4 7.811 2.712 11.173 ;
     RECT  1.824 11.173 2.712 11.315 ;
     RECT  7.8 2.137 8.424 12.323 ;
     RECT  12.672 10.213 13.512 13.379 ;
     RECT  14.832 12.517 14.856 14.675 ;
     RECT  2.4 11.315 2.712 19.449 ;
     RECT  5.1 2.151 5.412 19.449 ;
     RECT  7.8 12.323 8.112 19.449 ;
     RECT  10.5 2.151 10.812 19.449 ;
     RECT  13.2 13.379 13.512 19.449 ;
     RECT  15.9 2.151 16.212 19.449 ;
     RECT  18.6 2.151 18.912 19.449 ;
     RECT  2.4 19.449 2.52 19.463 ;
     RECT  5.1 19.449 5.22 19.463 ;
     RECT  7.8 19.449 7.92 19.463 ;
     RECT  10.5 19.449 10.62 19.463 ;
     RECT  13.2 19.449 13.32 19.463 ;
     RECT  15.9 19.449 16.02 19.463 ;
     RECT  18.6 19.449 18.72 19.463 ;
     RECT  2.304 7.811 2.4 8.533 ;
     RECT  0.18 8.533 1.152 8.771 ;
     RECT  1.176 8.533 2.4 8.771 ;
     RECT  10.812 8.965 12 10.019 ;
     RECT  12.024 8.965 13.2 10.019 ;
     RECT  12.672 10.019 13.2 10.213 ;
     RECT  13.512 12.517 14.832 14.675 ;
     RECT  14.856 12.517 15.9 14.675 ;
  END
END hbfd_rly_48_EW_rfc
END LIBRARY
